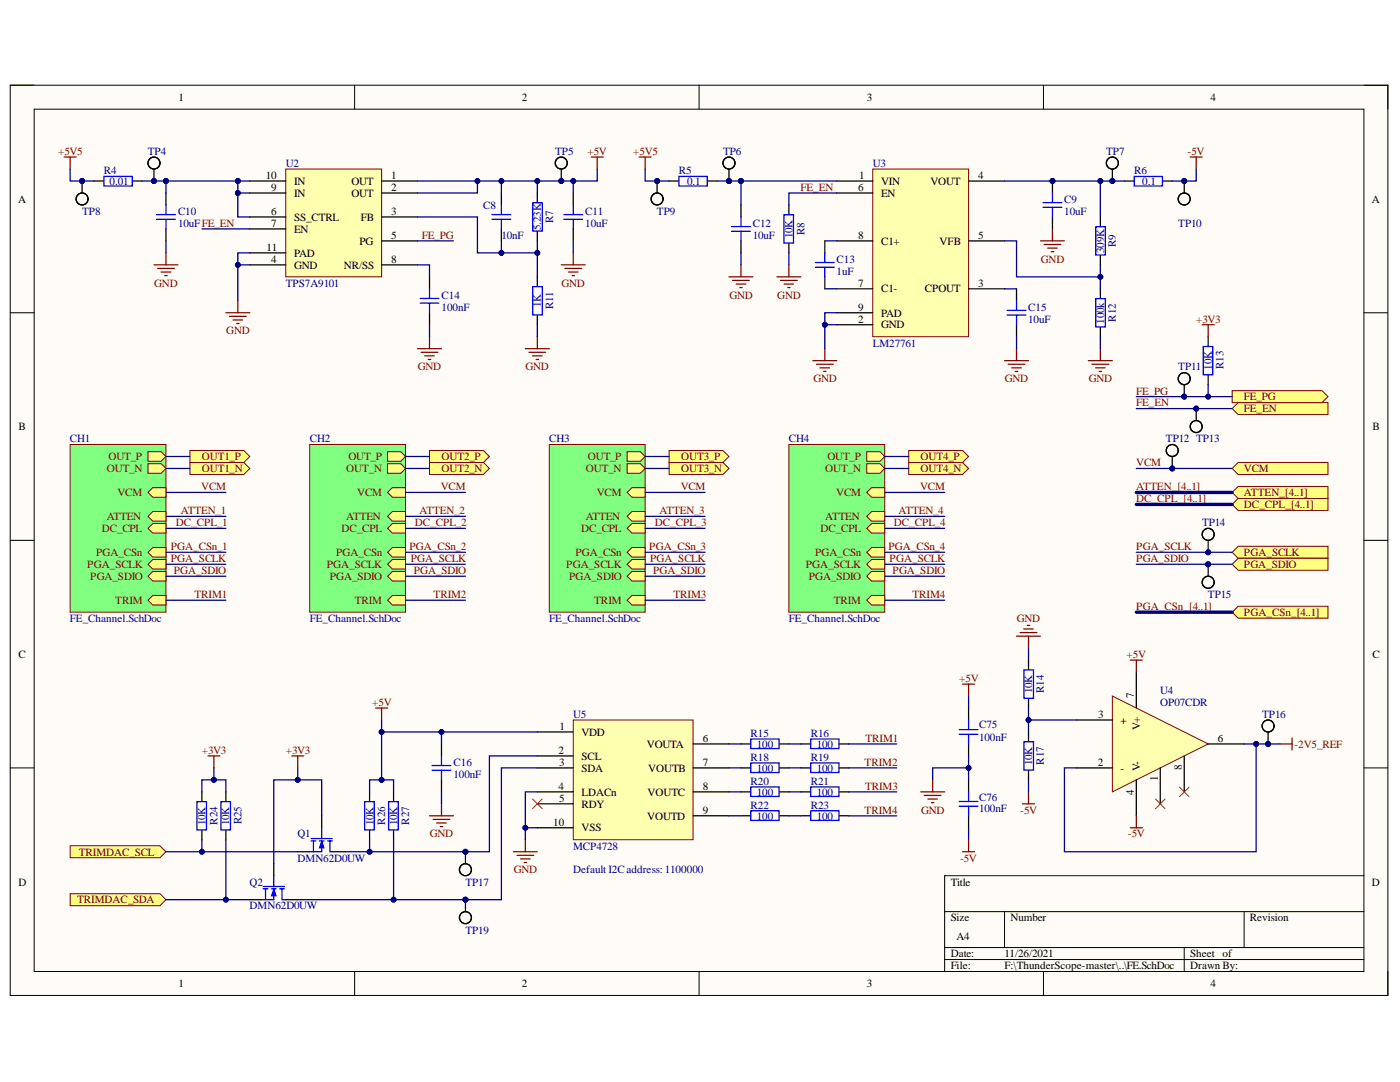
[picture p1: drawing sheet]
<svg xmlns="http://www.w3.org/2000/svg" width="279mm" height="216mm" viewBox="0 0 279 216" stroke-linecap="round" stroke-linejoin="round" font-family="sans-serif">
<defs><g id="words">
<g font-size="2.2">
<text x="35.6" y="20.1">1</text>
<text x="104.1" y="20.1">2</text>
<text x="173" y="20.1">3</text>
<text x="241.6" y="20.1">4</text>
<text x="53" y="35.7">10</text>
<text x="78.1" y="35.7">1</text>
<text x="171.5" y="35.7">1</text>
<text x="195.2" y="35.7">4</text>
<text x="3.6" y="40.4">A</text>
<text x="54.1" y="38.1">9</text>
<text x="58.7" y="39.2">IN</text>
<text x="58.7" y="36.9">IN</text>
<text x="70.1" y="36.9">OUT</text>
<text x="70.1" y="39.2">OUT</text>
<text x="78.1" y="38.1">2</text>
<text x="171.3" y="38.1">6</text>
<text x="175.9" y="36.9">VIN</text>
<text x="175.9" y="39.2">EN</text>
<text x="185.7" y="36.9">VOUT</text>
<text x="273.8" y="40.4">A</text>
<text x="54.1" y="42.9">6</text>
<text x="54.1" y="45.2">7</text>
<text x="58.7" y="44.1">SS_CTRL</text>
<text x="58.7" y="46.4">EN</text>
<text x="72" y="44.1">FB</text>
<text x="78.1" y="42.9">3</text>
<text x="78.1" y="47.6">5</text>
<text x="171.3" y="47.6">8</text>
<text x="195.2" y="47.6">5</text>
<text x="53.2" y="50.1">11</text>
<text x="54.1" y="52.4">4</text>
<text x="58.7" y="53.6">GND</text>
<text x="58.7" y="51.2">PAD</text>
<text x="68.6" y="53.6">NR/SS</text>
<text x="71.7" y="48.8">PG</text>
<text x="78.1" y="52.4">8</text>
<text x="175.9" y="48.8">C1+</text>
<text x="187.5" y="48.8">VFB</text>
<text x="171.3" y="57.2">7</text>
<text x="175.9" y="58.4">C1-</text>
<text x="184.6" y="58.4">CPOUT</text>
<text x="195.2" y="57.2">3</text>
<text x="171.3" y="64.4">2</text>
<text x="171.3" y="62">9</text>
<text x="175.9" y="65.5">GND</text>
<text x="175.9" y="63.2">PAD</text>
<text x="3.7" y="85.8">B</text>
<text x="273.9" y="85.8">B</text>
<text x="3.7" y="131.3">C</text>
<text x="273.9" y="131.3">C</text>
<text x="219.2" y="143.2">3</text>
<text x="226.3" y="139.4" transform="rotate(-90 226.3 139.4)">7</text>
<text x="111.7" y="145.6">1</text>
<text x="116.1" y="146.8">VDD</text>
<text x="129.1" y="149.2">VOUTA</text>
<text x="140.2" y="148">6</text>
<text x="223.6" y="144.4">+</text>
<text x="227.5" y="145.7" transform="rotate(-90 227.5 145.7)">V+</text>
<text x="243" y="148">6</text>
<text x="111.5" y="150.4">2</text>
<text x="111.6" y="152.8">3</text>
<text x="116.1" y="151.6">SCL</text>
<text x="116.1" y="154">SDA</text>
<text x="129.3" y="154">VOUTB</text>
<text x="140.2" y="152.8">7</text>
<text x="219.1" y="152.8">2</text>
<text x="223.6" y="154">-</text>
<text x="227.5" y="153.9" transform="rotate(-90 227.5 153.9)">V-</text>
<text x="231.1" y="155.9" transform="rotate(-90 231.1 155.9)">1</text>
<text x="235.8" y="153.7" transform="rotate(-90 235.8 153.7)">8</text>
<text x="111.5" y="157.5">4</text>
<text x="111.6" y="160">5</text>
<text x="116.1" y="158.8">LDACn</text>
<text x="116.1" y="161.2">RDY</text>
<text x="129.2" y="158.8">VOUTC</text>
<text x="140.2" y="157.5">8</text>
<text x="226.3" y="158.6" transform="rotate(-90 226.3 158.6)">4</text>
<text x="110.4" y="164.7">10</text>
<text x="116.1" y="165.9">VSS</text>
<text x="129.2" y="163.5">VOUTD</text>
<text x="140.2" y="162.4">9</text>
<text x="3.7" y="176.7">D</text>
<text x="189.7" y="176.7">Title</text>
<text x="273.8" y="176.7">D</text>
<text x="189.7" y="183.8">Size</text>
<text x="201.7" y="183.8">Number</text>
<text x="249.4" y="183.8">Revision</text>
<text x="189.7" y="191">Date:</text>
<text x="190.9" y="187.5">A4</text>
<text x="200.5" y="191">11/26/2021</text>
<text x="237.5" y="191">Sheet of</text>
<text x="35.6" y="197">1</text>
<text x="104.1" y="197">2</text>
<text x="173" y="197">3</text>
<text x="189.7" y="193.4">File:</text>
<text x="200.5" y="193.4">F:\ThunderScope-master\..\FE.SchDoc</text>
<text x="237.5" y="193.4">Drawn By:</text>
<text x="241.6" y="197">4</text>
</g>
<g font-size="2.2" fill="#800000">
<text x="11.6" y="30.9">+5V5</text>
<text x="117.2" y="30.9">+5V</text>
<text x="126.4" y="30.9">+5V5</text>
<text x="237" y="30.9">-5V</text>
<text x="159.8" y="38.1">FE_EN</text>
<text x="84.2" y="47.6">FE_PG</text>
<text x="207.7" y="52.4">GND</text>
<text x="30.8" y="57.2">GND</text>
<text x="112.1" y="57.2">GND</text>
<text x="145.6" y="59.6">GND</text>
<text x="155.1" y="59.6">GND</text>
<text x="238.7" y="64.4">+3V3</text>
<text x="45.2" y="66.7">GND</text>
<text x="83.4" y="73.9">GND</text>
<text x="104.9" y="73.9">GND</text>
<text x="162.3" y="76.3">GND</text>
<text x="200.6" y="76.3">GND</text>
<text x="217.3" y="76.3">GND</text>
<text x="226.8" y="81.1">FE_EN</text>
<text x="226.8" y="78.7">FE_PG</text>
<text x="248.3" y="82.3">FE_EN</text>
<text x="248.3" y="79.9">FE_PG</text>
<text x="21.3" y="94.2">OUT_N</text>
<text x="21.7" y="91.8">OUT_P</text>
<text x="40.3" y="94.2">OUT1_N</text>
<text x="40.3" y="91.8">OUT1_P</text>
<text x="69.1" y="94.2">OUT_N</text>
<text x="69.5" y="91.8">OUT_P</text>
<text x="88.1" y="94.2">OUT2_N</text>
<text x="88.1" y="91.8">OUT2_P</text>
<text x="116.9" y="94.2">OUT_N</text>
<text x="117.3" y="91.8">OUT_P</text>
<text x="135.9" y="94.2">OUT3_N</text>
<text x="135.9" y="91.8">OUT3_P</text>
<text x="164.7" y="94.2">OUT_N</text>
<text x="165.1" y="91.8">OUT_P</text>
<text x="183.7" y="94.2">OUT4_N</text>
<text x="183.7" y="91.8">OUT4_P</text>
<text x="226.8" y="93">VCM</text>
<text x="248.3" y="94.2">VCM</text>
<text x="23.4" y="99">VCM</text>
<text x="40.2" y="97.8">VCM</text>
<text x="71.3" y="99">VCM</text>
<text x="88" y="97.8">VCM</text>
<text x="119.1" y="99">VCM</text>
<text x="135.8" y="97.8">VCM</text>
<text x="166.9" y="99">VCM</text>
<text x="183.6" y="97.8">VCM</text>
<text x="226.8" y="97.8">ATTEN_[4..1]</text>
<text x="226.8" y="100.2">DC_CPL_[4..1]</text>
<text x="248.3" y="99">ATTEN_[4..1]</text>
<text x="248.3" y="101.4">DC_CPL_[4..1]</text>
<text x="20.3" y="106.2">DC_CPL</text>
<text x="21.3" y="103.8">ATTEN</text>
<text x="35.1" y="105">DC_CPL_1</text>
<text x="36.1" y="102.6">ATTEN_1</text>
<text x="68.2" y="106.2">DC_CPL</text>
<text x="69.1" y="103.8">ATTEN</text>
<text x="82.8" y="105">DC_CPL_2</text>
<text x="83.7" y="102.6">ATTEN_2</text>
<text x="116" y="106.2">DC_CPL</text>
<text x="116.9" y="103.8">ATTEN</text>
<text x="130.7" y="105">DC_CPL_3</text>
<text x="131.6" y="102.6">ATTEN_3</text>
<text x="163.8" y="106.2">DC_CPL</text>
<text x="164.7" y="103.8">ATTEN</text>
<text x="178.4" y="105">DC_CPL_4</text>
<text x="179.3" y="102.6">ATTEN_4</text>
<text x="17.4" y="113.4">PGA_SCLK</text>
<text x="19.2" y="110.9">PGA_CSn</text>
<text x="34.1" y="112.1">PGA_SCLK</text>
<text x="34.1" y="109.8">PGA_CSn_1</text>
<text x="65.2" y="113.4">PGA_SCLK</text>
<text x="67.1" y="110.9">PGA_CSn</text>
<text x="81.7" y="109.8">PGA_CSn_2</text>
<text x="82" y="112.1">PGA_SCLK</text>
<text x="113" y="113.4">PGA_SCLK</text>
<text x="114.9" y="110.9">PGA_CSn</text>
<text x="129.6" y="109.8">PGA_CSn_3</text>
<text x="129.8" y="112.1">PGA_SCLK</text>
<text x="160.8" y="113.4">PGA_SCLK</text>
<text x="162.7" y="110.9">PGA_CSn</text>
<text x="177.3" y="109.8">PGA_CSn_4</text>
<text x="177.5" y="112.1">PGA_SCLK</text>
<text x="226.8" y="109.8">PGA_SCLK</text>
<text x="226.8" y="112.1">PGA_SDIO</text>
<text x="248.3" y="110.9">PGA_SCLK</text>
<text x="248.3" y="113.4">PGA_SDIO</text>
<text x="18" y="115.8">PGA_SDIO</text>
<text x="34.7" y="114.6">PGA_SDIO</text>
<text x="38.8" y="119.3">TRIM1</text>
<text x="65.8" y="115.8">PGA_SDIO</text>
<text x="82.6" y="114.6">PGA_SDIO</text>
<text x="86.5" y="119.3">TRIM2</text>
<text x="113.6" y="115.8">PGA_SDIO</text>
<text x="130.3" y="114.6">PGA_SDIO</text>
<text x="134.4" y="119.3">TRIM3</text>
<text x="161.4" y="115.8">PGA_SDIO</text>
<text x="178.1" y="114.6">PGA_SDIO</text>
<text x="182.1" y="119.3">TRIM4</text>
<text x="23" y="120.5">TRIM</text>
<text x="70.8" y="120.5">TRIM</text>
<text x="118.6" y="120.5">TRIM</text>
<text x="166.4" y="120.5">TRIM</text>
<text x="202.9" y="124.1">GND</text>
<text x="226.8" y="121.7">PGA_CSn_[4..1]</text>
<text x="248.3" y="123">PGA_CSn_[4..1]</text>
<text x="224.8" y="131.3">+5V</text>
<text x="191.4" y="136.1">+5V</text>
<text x="74.3" y="140.9">+5V</text>
<text x="172.7" y="148">TRIM1</text>
<text x="258.3" y="149.2">-2V5_REF</text>
<text x="40.3" y="150.4">+3V3</text>
<text x="57" y="150.4">+3V3</text>
<text x="172.6" y="152.8">TRIM2</text>
<text x="172.6" y="157.5">TRIM3</text>
<text x="85.8" y="167.1">GND</text>
<text x="172.6" y="162.4">TRIM4</text>
<text x="183.8" y="162.4">GND</text>
<text x="203.6" y="162.4">-5V</text>
<text x="225.1" y="167.1">-5V</text>
<text x="15.7" y="170.7">TRIMDAC_SCL</text>
<text x="191.6" y="171.9">-5V</text>
<text x="102.5" y="174.3">GND</text>
<text x="15.4" y="180.3">TRIMDAC_SDA</text>
</g>
<g font-size="2.2" fill="#000080">
<text x="20.7" y="34.8">R4</text>
<text x="29.5" y="30.9">TP4</text>
<text x="57" y="33.3">U2</text>
<text x="110.8" y="30.9">TP5</text>
<text x="135.5" y="34.8">R5</text>
<text x="144.3" y="30.9">TP6</text>
<text x="174.2" y="33.3">U3</text>
<text x="220.8" y="30.9">TP7</text>
<text x="226.4" y="34.8">R6</text>
<text x="21.8" y="36.9">0.01</text>
<text x="96.4" y="41.7">C8</text>
<text x="137.1" y="36.9">0.1</text>
<text x="212.4" y="40.4">C9</text>
<text x="228" y="36.9">0.1</text>
<text x="16.4" y="42.9">TP8</text>
<text x="35.5" y="42.9">C10</text>
<text x="35.5" y="45.2">10uFFE_EN</text>
<text x="100.1" y="47.6">10nF</text>
<text x="107.9" y="45.9" transform="rotate(-90 107.9 45.9)">5.23K</text>
<text x="110.4" y="44.5" transform="rotate(-90 110.4 44.5)">R7</text>
<text x="116.8" y="42.9">C11</text>
<text x="116.8" y="45.2">10uF</text>
<text x="131.1" y="42.9">TP9</text>
<text x="150.2" y="45.2">C12</text>
<text x="150.2" y="47.6">10uF</text>
<text x="158.2" y="47.5" transform="rotate(-90 158.2 47.5)">10K</text>
<text x="160.5" y="46.9" transform="rotate(-90 160.5 46.9)">R8</text>
<text x="212.4" y="42.9">10uF</text>
<text x="235.2" y="45.2">TP10</text>
<text x="167" y="52.4">C13</text>
<text x="220.3" y="50.5" transform="rotate(-90 220.3 50.5)">309K</text>
<text x="222.7" y="49.3" transform="rotate(-90 222.7 49.3)">R9</text>
<text x="57" y="57.2">TPS7A9101</text>
<text x="88.1" y="59.6">C14</text>
<text x="167" y="54.8">1uF</text>
<text x="88.1" y="62">100nF</text>
<text x="107.9" y="61.3" transform="rotate(-90 107.9 61.3)">1K</text>
<text x="110.4" y="61.6" transform="rotate(-90 110.4 61.6)">R11</text>
<text x="205.2" y="62">C15</text>
<text x="205.2" y="64.4">10uF</text>
<text x="220.3" y="64.6" transform="rotate(-90 220.3 64.6)">100k</text>
<text x="222.7" y="64.2" transform="rotate(-90 222.7 64.2)">R12</text>
<text x="174.2" y="69.2">LM27761</text>
<text x="235.2" y="73.9">TP11</text>
<text x="241.8" y="73.8" transform="rotate(-90 241.8 73.8)">10K</text>
<text x="244.2" y="73.7" transform="rotate(-90 244.2 73.7)">R13</text>
<text x="14" y="88.3">CH1</text>
<text x="61.8" y="88.3">CH2</text>
<text x="109.6" y="88.3">CH3</text>
<text x="157.4" y="88.3">CH4</text>
<text x="232.7" y="88.3">TP12 TP13</text>
<text x="239.9" y="105">TP14</text>
<text x="241.1" y="119.3">TP15</text>
<text x="14" y="124.1">FE_Channel.SchDoc</text>
<text x="61.8" y="124.1">FE_Channel.SchDoc</text>
<text x="109.6" y="124.1">FE_Channel.SchDoc</text>
<text x="157.4" y="124.1">FE_Channel.SchDoc</text>
<text x="114.4" y="143.2">U5</text>
<text x="206" y="138.3" transform="rotate(-90 206 138.3)">10K</text>
<text x="208.3" y="138.3" transform="rotate(-90 208.3 138.3)">R14</text>
<text x="231.5" y="138.4">U4</text>
<text x="231.5" y="140.9">OP07CDR</text>
<text x="251.9" y="143.2">TP16</text>
<text x="149.8" y="147.1">R15</text>
<text x="151.1" y="149.2">100</text>
<text x="161.8" y="147.1">R16</text>
<text x="163" y="149.2">100</text>
<text x="195.4" y="145.4">C75</text>
<text x="195.4" y="147.8">100nF</text>
<text x="90.5" y="152.8">C16</text>
<text x="90.5" y="155.2">100nF</text>
<text x="149.8" y="151.8">R18</text>
<text x="151.1" y="154">100</text>
<text x="161.8" y="151.8">R19</text>
<text x="163" y="154">100</text>
<text x="206" y="152.7" transform="rotate(-90 206 152.7)">10K</text>
<text x="208.3" y="152.5" transform="rotate(-90 208.3 152.5)">R17</text>
<text x="149.8" y="156.6">R20</text>
<text x="149.8" y="161.3">R22</text>
<text x="151.1" y="158.8">100</text>
<text x="161.8" y="156.6">R21</text>
<text x="161.8" y="161.3">R23</text>
<text x="163" y="158.8">100</text>
<text x="195.4" y="159.7">C76</text>
<text x="41" y="164.6" transform="rotate(-90 41 164.6)">10K</text>
<text x="43.4" y="164.6" transform="rotate(-90 43.4 164.6)">R24</text>
<text x="45.8" y="164.6" transform="rotate(-90 45.8 164.6)">10K</text>
<text x="48.2" y="164.5" transform="rotate(-90 48.2 164.5)">R25</text>
<text x="59.4" y="167.1">Q1</text>
<text x="74.5" y="164.6" transform="rotate(-90 74.5 164.6)">10K</text>
<text x="76.9" y="164.6" transform="rotate(-90 76.9 164.6)">R26</text>
<text x="79.3" y="164.6" transform="rotate(-90 79.3 164.6)">10K</text>
<text x="81.6" y="164.6" transform="rotate(-90 81.6 164.6)">R27</text>
<text x="151.1" y="163.5">100</text>
<text x="163" y="163.5">100</text>
<text x="195.4" y="162.1">100nF</text>
<text x="59.4" y="171.9">DMN62D0UW</text>
<text x="114.4" y="169.5">MCP4728</text>
<text x="49.8" y="176.7">Q2</text>
<text x="92.9" y="176.7">TP17</text>
<text x="114.4" y="174.3">Default I2Caddress: 1100000</text>
<text x="49.8" y="181.5">DMN62D0UW</text>
<text x="92.9" y="186.3">TP19</text>
</g>
</g></defs>
<path d="M2 17h275v181.6h-275z" fill-rule="evenodd" fill="#fffcf8"/>
<path d="M2 17h275v181.6h-275z" fill="none" stroke="#000" stroke-width=".2"/>
<path d="M6.8 21.8h265.4v172.1h-265.4z" fill-rule="evenodd" fill="#fffcf8"/>
<g fill="none" stroke="#000" stroke-width=".2">
<path d="M2 17h4.8M70.8 17v4.8M139.5 17v4.8M208.2 17v4.8M272.2 17h4.8v4.8M6.8 21.8h265.4v172.1h-265.4zM2 62.4h4.8M272.2 62.4h4.8M2 107.8h4.8M272.2 107.8h4.8M2 153.2h4.8M272.2 153.2h4.8"/>
<path d="M272.2 174.7h-83.7v19.2M70.8 193.9v4.7M139.5 193.9v4.7M188.5 181.9h83.7M188.5 189.1h83.7M188.5 191.5h83.7M200.5 181.9v7.2M208.2 193.9v4.7M236.3 189.1v4.8M248.3 181.9v7.2M277 193.9v4.7"/>
</g>
<path d="M14 88.7h19.1v33.5h-19.1z" fill-rule="evenodd" fill="#80ff80"/>
<path d="M14 88.7h19.1v33.5h-19.1z" fill="none" stroke="#800000" stroke-width=".2"/>
<path d="M29.5 90.1h2.7l.9 1-.9 .9h-2.7z" fill-rule="evenodd" fill="#ffff80"/>
<path d="M29.5 90.1h2.7l.9 1-.9 .9h-2.7z" fill="none" stroke="#800000" stroke-width=".2"/>
<path d="M29.5 98.3l1-1h2.6v1.9h-2.6z" fill-rule="evenodd" fill="#ffff80"/>
<path d="M29.5 98.3l1-1h2.6v1.9h-2.6z" fill="none" stroke="#800000" stroke-width=".2"/>
<path d="M29.5 92.5h2.7l.9 1-.9 .9h-2.7z" fill-rule="evenodd" fill="#ffff80"/>
<path d="M29.5 92.5h2.7l.9 1-.9 .9h-2.7z" fill="none" stroke="#800000" stroke-width=".2"/>
<path d="M29.5 119.8l1-1h2.6v1.9h-2.6z" fill-rule="evenodd" fill="#ffff80"/>
<path d="M29.5 119.8l1-1h2.6v1.9h-2.6z" fill="none" stroke="#800000" stroke-width=".2"/>
<path d="M29.5 103l1-.9h2.6v1.9h-2.6z" fill-rule="evenodd" fill="#ffff80"/>
<path d="M29.5 103l1-.9h2.6v1.9h-2.6z" fill="none" stroke="#800000" stroke-width=".2"/>
<path d="M29.5 105.4l1-.9h2.6v1.9h-2.6z" fill-rule="evenodd" fill="#ffff80"/>
<path d="M29.5 105.4l1-.9h2.6v1.9h-2.6z" fill="none" stroke="#800000" stroke-width=".2"/>
<path d="M29.5 110.2l1-1h2.6v2h-2.6z" fill-rule="evenodd" fill="#ffff80"/>
<path d="M29.5 110.2l1-1h2.6v2h-2.6z" fill="none" stroke="#800000" stroke-width=".2"/>
<path d="M29.5 112.6l1-1h2.6v2h-2.6z" fill-rule="evenodd" fill="#ffff80"/>
<path d="M29.5 112.6l1-1h2.6v2h-2.6z" fill="none" stroke="#800000" stroke-width=".2"/>
<path d="M29.5 115l1-1h2.6v1.9h-2.6z" fill-rule="evenodd" fill="#ffff80"/>
<path d="M29.5 115l1-1h2.6v1.9h-2.6z" fill="none" stroke="#800000" stroke-width=".2"/>
<path d="M88.1 148.4v2.4M88.1 155.6v2.4M147.9 148.4h1.9M155.6 148.4h1.8M159.8 148.4h1.9M167.5 148.4h1.9M59.4 170h2.4M64.2 162.8v2.4M66.6 170h2.4" fill="none" stroke="#000" stroke-width=".25"/>
<g fill="none" stroke="#00f" stroke-width=".25">
<path d="M86.2 153.7h3.8M86.2 152.8h3.8M88.1 150.8v2M88.1 153.7v1.9M149.8 147.5h5.7v1.9h-5.7zM161.8 147.5h5.6v1.9h-5.6zM62.1 167.3h4.2M62.1 167.8h.9M62.6 167.8v2.2M63.7 167.8h1M64.2 165.2v2.1M64.2 167.8v2.2h-2.4"/>
<path d="M65.4 167.8h.9M65.8 167.8v2.2"/>
</g>
<path d="M85.7 162.8h4.8M86.4 163.5h3.4M87.2 164.2h1.9M87.9 164.9h.4M88.1 160.4v2.4M102.5 170h4.7M103.2 170.7h3.3M103.9 171.4h1.9M104.6 172.1h.5M104.8 167.6v2.4" fill="none" stroke="#800000" stroke-width=".25"/>
<path d="M64.2 167.8l.5 1.4h-1z" fill="#00f"/>
<path d="M64.2 167.8l.5 1.4h-1z" fill="none" stroke="#00f" stroke-width=".2"/>
<path d="M52.5 176.9h4.3M52.5 177.4h1M53 177.4v2.1M54.2 177.4h.9M54.6 174.7v2.2M54.6 177.4v2.1h-2.4M55.8 177.4h1M56.3 177.4v2.1M65.9 170h.7" fill="none" stroke="#00f" stroke-width=".25"/>
<path d="M49.9 179.5h2.3M54.6 172.3v2.4M57 179.5h2.4" fill="none" stroke="#000" stroke-width=".25"/>
<path d="M54.6 177.4l.5 1.4h-.9z" fill="#00f"/>
<path d="M54.6 177.4l.5 1.4h-.9z" fill="none" stroke="#00f" stroke-width=".2"/>
<path d="M39.3 160h1.9v5.6h-1.9zM44.1 160h1.9v5.6h-1.9zM72.8 160h1.9v5.6h-1.9zM77.6 160h1.9v5.6h-1.9zM56.3 179.5h.7" fill="none" stroke="#00f" stroke-width=".25"/>
<path d="M40.3 158v1.9M45.1 158v1.9M73.8 158v1.9M78.5 158v1.9M40.3 165.7v1.9M45.1 165.7v1.9M73.8 165.7v1.9M78.5 165.7v1.9" fill="none" stroke="#000" stroke-width=".25"/>
<path d="M41.5 150.8h2.4M42.7 150.8v2.4M58.2 150.8h2.4M59.4 150.8v2.4M75 141.3h2.3M76.2 141.3v2.4" fill="none" stroke="#800000" stroke-width=".25"/>
<path d="M14 168.8h17.9l1.2 1.2-1.2 1.2h-17.9z" fill-rule="evenodd" fill="#ffff80"/>
<path d="M14 168.8h17.9l1.2 1.2-1.2 1.2h-17.9z" fill="none" stroke="#800000" stroke-width=".2"/>
<path d="M14 178.3h17.9l1.2 1.2-1.2 1.2h-17.9z" fill-rule="evenodd" fill="#ffff80"/>
<path d="M14 178.3h17.9l1.2 1.2-1.2 1.2h-17.9z" fill="none" stroke="#800000" stroke-width=".2"/>
<path d="M222 138.9l19.1 9.5-19.1 9.6z" fill="#ffffb0"/>
<path d="M222 138.9l19.1 9.5-19.1 9.6z" fill="none" stroke="#800000" stroke-width=".2"/>
<path d="M205.3 131.7v1.9M205.3 139.4v1.9M226.8 134.1v7.2M205.3 146.1v1.8M205.3 153.7v1.9M214.8 143.7h7.2M214.8 153.2h7.2M226.8 155.6v7.2M231.6 153.2v7.2M236.3 150.8v7.2M241.1 148.4h7.2" fill="none" stroke="#000" stroke-width=".25"/>
<g fill="none" stroke="#800000" stroke-width=".25">
<path d="M202.9 126.9h4.8M203.6 126.2h3.3M204.3 125.5h1.9M205 124.8h.5M205.3 126.9v2.4M225.6 131.7h2.4M226.8 131.7v2.4M205.3 158v2.4M255.5 148.4h2.4M257.9 147.3v2.3M204.1 160.4h2.4M225.6 165.2h2.4"/>
<path d="M226.8 162.8v2.4"/>
</g>
<path d="M230.6 159.4l1.9 2M232.5 159.4l-1.9 2M235.4 157.1l1.9 1.9M237.3 157.1l-1.9 1.9" fill="none" stroke="#f00" stroke-width=".2"/>
<path d="M204.3 133.7h2v5.6h-2zM204.3 148h2v5.7h-2z" fill="none" stroke="#00f" stroke-width=".25"/>
<path d="M61.8 88.7h19.1v33.5h-19.1z" fill-rule="evenodd" fill="#80ff80"/>
<path d="M61.8 88.7h19.1v33.5h-19.1z" fill="none" stroke="#800000" stroke-width=".2"/>
<path d="M77.3 90.1h2.7l.9 1-.9 .9h-2.7z" fill-rule="evenodd" fill="#ffff80"/>
<path d="M77.3 90.1h2.7l.9 1-.9 .9h-2.7z" fill="none" stroke="#800000" stroke-width=".2"/>
<path d="M77.3 98.3l1-1h2.6v1.9h-2.6z" fill-rule="evenodd" fill="#ffff80"/>
<path d="M77.3 98.3l1-1h2.6v1.9h-2.6z" fill="none" stroke="#800000" stroke-width=".2"/>
<path d="M77.3 92.5h2.7l.9 1-.9 .9h-2.7z" fill-rule="evenodd" fill="#ffff80"/>
<path d="M77.3 92.5h2.7l.9 1-.9 .9h-2.7z" fill="none" stroke="#800000" stroke-width=".2"/>
<path d="M77.3 119.8l1-1h2.6v1.9h-2.6z" fill-rule="evenodd" fill="#ffff80"/>
<path d="M77.3 119.8l1-1h2.6v1.9h-2.6z" fill="none" stroke="#800000" stroke-width=".2"/>
<path d="M77.3 103l1-.9h2.6v1.9h-2.6z" fill-rule="evenodd" fill="#ffff80"/>
<path d="M77.3 103l1-.9h2.6v1.9h-2.6z" fill="none" stroke="#800000" stroke-width=".2"/>
<path d="M77.3 105.4l1-.9h2.6v1.9h-2.6z" fill-rule="evenodd" fill="#ffff80"/>
<path d="M77.3 105.4l1-.9h2.6v1.9h-2.6z" fill="none" stroke="#800000" stroke-width=".2"/>
<path d="M77.3 110.2l1-1h2.6v2h-2.6z" fill-rule="evenodd" fill="#ffff80"/>
<path d="M77.3 110.2l1-1h2.6v2h-2.6z" fill="none" stroke="#800000" stroke-width=".2"/>
<path d="M77.3 112.6l1-1h2.6v2h-2.6z" fill-rule="evenodd" fill="#ffff80"/>
<path d="M77.3 112.6l1-1h2.6v2h-2.6z" fill="none" stroke="#800000" stroke-width=".2"/>
<path d="M77.3 115l1-1h2.6v1.9h-2.6z" fill-rule="evenodd" fill="#ffff80"/>
<path d="M77.3 115l1-1h2.6v1.9h-2.6z" fill="none" stroke="#800000" stroke-width=".2"/>
<path d="M109.6 88.7h19.2v33.5h-19.2z" fill-rule="evenodd" fill="#80ff80"/>
<path d="M109.6 88.7h19.2v33.5h-19.2z" fill="none" stroke="#800000" stroke-width=".2"/>
<path d="M125.2 90.1h2.6l1 1-1 .9h-2.6z" fill-rule="evenodd" fill="#ffff80"/>
<path d="M125.2 90.1h2.6l1 1-1 .9h-2.6z" fill="none" stroke="#800000" stroke-width=".2"/>
<path d="M125.2 98.3l.9-1h2.7v1.9h-2.7z" fill-rule="evenodd" fill="#ffff80"/>
<path d="M125.2 98.3l.9-1h2.7v1.9h-2.7z" fill="none" stroke="#800000" stroke-width=".2"/>
<path d="M125.2 92.5h2.6l1 1-1 .9h-2.6z" fill-rule="evenodd" fill="#ffff80"/>
<path d="M125.2 92.5h2.6l1 1-1 .9h-2.6z" fill="none" stroke="#800000" stroke-width=".2"/>
<path d="M125.2 119.8l.9-1h2.7v1.9h-2.7z" fill-rule="evenodd" fill="#ffff80"/>
<path d="M125.2 119.8l.9-1h2.7v1.9h-2.7z" fill="none" stroke="#800000" stroke-width=".2"/>
<path d="M125.2 103l.9-.9h2.7v1.9h-2.7z" fill-rule="evenodd" fill="#ffff80"/>
<path d="M125.2 103l.9-.9h2.7v1.9h-2.7z" fill="none" stroke="#800000" stroke-width=".2"/>
<path d="M125.2 105.4l.9-.9h2.7v1.9h-2.7z" fill-rule="evenodd" fill="#ffff80"/>
<path d="M125.2 105.4l.9-.9h2.7v1.9h-2.7z" fill="none" stroke="#800000" stroke-width=".2"/>
<path d="M125.2 110.2l.9-1h2.7v2h-2.7z" fill-rule="evenodd" fill="#ffff80"/>
<path d="M125.2 110.2l.9-1h2.7v2h-2.7z" fill="none" stroke="#800000" stroke-width=".2"/>
<path d="M125.2 112.6l.9-1h2.7v2h-2.7z" fill-rule="evenodd" fill="#ffff80"/>
<path d="M125.2 112.6l.9-1h2.7v2h-2.7z" fill="none" stroke="#800000" stroke-width=".2"/>
<path d="M125.2 115l.9-1h2.7v1.9h-2.7z" fill-rule="evenodd" fill="#ffff80"/>
<path d="M125.2 115l.9-1h2.7v1.9h-2.7z" fill="none" stroke="#800000" stroke-width=".2"/>
<path d="M157.4 88.7h19.2v33.5h-19.2z" fill-rule="evenodd" fill="#80ff80"/>
<path d="M157.4 88.7h19.2v33.5h-19.2z" fill="none" stroke="#800000" stroke-width=".2"/>
<path d="M173 90.1h2.6l1 1-1 .9h-2.6z" fill-rule="evenodd" fill="#ffff80"/>
<path d="M173 90.1h2.6l1 1-1 .9h-2.6z" fill="none" stroke="#800000" stroke-width=".2"/>
<path d="M173 98.3l.9-1h2.7v1.9h-2.7z" fill-rule="evenodd" fill="#ffff80"/>
<path d="M173 98.3l.9-1h2.7v1.9h-2.7z" fill="none" stroke="#800000" stroke-width=".2"/>
<path d="M173 92.5h2.6l1 1-1 .9h-2.6z" fill-rule="evenodd" fill="#ffff80"/>
<path d="M173 92.5h2.6l1 1-1 .9h-2.6z" fill="none" stroke="#800000" stroke-width=".2"/>
<path d="M173 119.8l.9-1h2.7v1.9h-2.7z" fill-rule="evenodd" fill="#ffff80"/>
<path d="M173 119.8l.9-1h2.7v1.9h-2.7z" fill="none" stroke="#800000" stroke-width=".2"/>
<path d="M173 103l.9-.9h2.7v1.9h-2.7z" fill-rule="evenodd" fill="#ffff80"/>
<path d="M173 103l.9-.9h2.7v1.9h-2.7z" fill="none" stroke="#800000" stroke-width=".2"/>
<path d="M173 105.4l.9-.9h2.7v1.9h-2.7z" fill-rule="evenodd" fill="#ffff80"/>
<path d="M173 105.4l.9-.9h2.7v1.9h-2.7z" fill="none" stroke="#800000" stroke-width=".2"/>
<path d="M173 110.2l.9-.9h2.7v1.9h-2.7z" fill-rule="evenodd" fill="#ffff80"/>
<path d="M173 110.2l.9-.9h2.7v1.9h-2.7z" fill="none" stroke="#800000" stroke-width=".2"/>
<path d="M173 112.6l.9-1h2.7v2h-2.7z" fill-rule="evenodd" fill="#ffff80"/>
<path d="M173 112.6l.9-1h2.7v2h-2.7z" fill="none" stroke="#800000" stroke-width=".2"/>
<path d="M173 115l.9-1h2.7v1.9h-2.7z" fill-rule="evenodd" fill="#ffff80"/>
<path d="M173 115l.9-1h2.7v1.9h-2.7z" fill="none" stroke="#800000" stroke-width=".2"/>
<path d="M114.4 143.7h23.9v23.9h-23.9z" fill-rule="evenodd" fill="#ffffb0"/>
<path d="M114.4 143.7h23.9v23.9h-23.9z" fill="none" stroke="#800000" stroke-width=".2"/>
<g fill="none" stroke="#000" stroke-width=".25">
<path d="M107.2 146.1h7.2M107.2 150.8h7.2M107.2 153.2h7.2M107.2 158h7.2M138.3 153.2h7.2M138.3 158h7.2M138.3 148.4h7.2M147.9 153.2h1.9M147.9 158h1.9M155.6 153.2h1.8M155.6 158h1.8M159.8 153.2h1.9"/>
<path d="M159.8 158h1.9M167.5 153.2h1.9M167.5 158h1.9M107.2 160.4h7.2M107.2 165.2h7.2M138.3 162.8h7.2M147.9 162.8h1.9M155.6 162.8h1.8M159.8 162.8h1.9M167.5 162.8h1.9"/>
</g>
<path d="M149.8 152.2h5.7v1.9h-5.7zM149.8 157h5.7v1.9h-5.7zM161.8 152.2h5.6v1.9h-5.6zM161.8 157h5.6v1.9h-5.6zM149.8 161.8h5.7v1.9h-5.7zM161.8 161.8h5.6v1.9h-5.6z" fill="none" stroke="#00f" stroke-width=".25"/>
<path d="M106.3 159.4l1.9 2M108.2 159.4l-1.9 2" fill="none" stroke="#f00" stroke-width=".2"/>
<path d="M245.9 98.3l1.2-1.2h17.9v2.4h-17.9z" fill-rule="evenodd" fill="#ffff80"/>
<path d="M245.9 98.3l1.2-1.2h17.9v2.4h-17.9z" fill="none" stroke="#800000" stroke-width=".2"/>
<path d="M245.9 100.7l1.2-1.2h17.9v2.3h-17.9z" fill-rule="evenodd" fill="#ffff80"/>
<path d="M245.9 100.7l1.2-1.2h17.9v2.3h-17.9z" fill="none" stroke="#800000" stroke-width=".2"/>
<path d="M245.9 110.2l1.2-1.2h17.9v2.4h-17.9z" fill-rule="evenodd" fill="#ffff80"/>
<path d="M245.9 110.2l1.2-1.2h17.9v2.4h-17.9z" fill="none" stroke="#800000" stroke-width=".2"/>
<path d="M245.9 112.6l1.2-1.2h17.9v2.4h-17.9z" fill-rule="evenodd" fill="#ffff80"/>
<path d="M245.9 112.6l1.2-1.2h17.9v2.4h-17.9z" fill="none" stroke="#800000" stroke-width=".2"/>
<path d="M245.9 122.2l1.2-1.2h17.9v2.4h-17.9z" fill-rule="evenodd" fill="#ffff80"/>
<path d="M245.9 122.2l1.2-1.2h17.9v2.4h-17.9z" fill="none" stroke="#800000" stroke-width=".2"/>
<path d="M245.9 93.5l1.2-1.2h17.9v2.4h-17.9z" fill-rule="evenodd" fill="#ffff80"/>
<path d="M245.9 93.5l1.2-1.2h17.9v2.4h-17.9z" fill="none" stroke="#800000" stroke-width=".2"/>
<path d="M37.9 92.3h10.8l1.2 1.2-1.2 1.2h-10.8z" fill-rule="evenodd" fill="#ffff80"/>
<path d="M37.9 92.3h10.8l1.2 1.2-1.2 1.2h-10.8z" fill="none" stroke="#800000" stroke-width=".2"/>
<path d="M37.9 89.9h10.8l1.2 1.2-1.2 1.2h-10.8z" fill-rule="evenodd" fill="#ffff80"/>
<path d="M37.9 89.9h10.8l1.2 1.2-1.2 1.2h-10.8z" fill="none" stroke="#800000" stroke-width=".2"/>
<path d="M85.7 92.3h10.8l1.2 1.2-1.2 1.2h-10.8z" fill-rule="evenodd" fill="#ffff80"/>
<path d="M85.7 92.3h10.8l1.2 1.2-1.2 1.2h-10.8z" fill="none" stroke="#800000" stroke-width=".2"/>
<path d="M85.7 89.9h10.8l1.2 1.2-1.2 1.2h-10.8z" fill-rule="evenodd" fill="#ffff80"/>
<path d="M85.7 89.9h10.8l1.2 1.2-1.2 1.2h-10.8z" fill="none" stroke="#800000" stroke-width=".2"/>
<path d="M133.5 92.3h10.8l1.2 1.2-1.2 1.2h-10.8z" fill-rule="evenodd" fill="#ffff80"/>
<path d="M133.5 92.3h10.8l1.2 1.2-1.2 1.2h-10.8z" fill="none" stroke="#800000" stroke-width=".2"/>
<path d="M133.5 89.9h10.8l1.2 1.2-1.2 1.2h-10.8z" fill-rule="evenodd" fill="#ffff80"/>
<path d="M133.5 89.9h10.8l1.2 1.2-1.2 1.2h-10.8z" fill="none" stroke="#800000" stroke-width=".2"/>
<path d="M181.4 92.3h10.7l1.2 1.2-1.2 1.2h-10.7z" fill-rule="evenodd" fill="#ffff80"/>
<path d="M181.4 92.3h10.7l1.2 1.2-1.2 1.2h-10.7z" fill="none" stroke="#800000" stroke-width=".2"/>
<path d="M181.4 89.9h10.7l1.2 1.2-1.2 1.2h-10.7z" fill-rule="evenodd" fill="#ffff80"/>
<path d="M181.4 89.9h10.7l1.2 1.2-1.2 1.2h-10.7z" fill="none" stroke="#800000" stroke-width=".2"/>
<path d="M245.9 81.5l1.2-1.2h17.9v2.4h-17.9z" fill-rule="evenodd" fill="#ffff80"/>
<path d="M245.9 81.5l1.2-1.2h17.9v2.4h-17.9z" fill="none" stroke="#800000" stroke-width=".2"/>
<path d="M174.2 33.7h19.1v33.5h-19.1z" fill-rule="evenodd" fill="#ffffb0"/>
<path d="M174.2 33.7h19.1v33.5h-19.1z" fill="none" stroke="#800000" stroke-width=".2"/>
<g fill="none" stroke="#000" stroke-width=".25">
<path d="M167 36.1h7.2M167 38.5h7.2M193.3 36.1h7.2M147.9 40.9v2.4M147.9 48.1v2.4M164.6 48.1v2.4M164.6 55.2v2.4M167 57.6h7.2M167 48.1h7.2M193.3 57.6h7.2M193.3 48.1h7.2M202.9 57.6v2.4"/>
<path d="M219.6 43.3v1.9M219.6 51v1.9M219.6 57.6v1.9M167 64.8h7.2M167 62.4h7.2M202.9 64.8v2.4M219.6 65.3v1.9"/>
</g>
<g fill="none" stroke="#00f" stroke-width=".25">
<path d="M146 46.1h3.8M146 45.2h3.8M147.9 43.3v1.9M147.9 46.1v2M162.7 53.3h3.8M162.7 52.4h3.8M164.6 50.5v1.9M164.6 53.3v1.9M218.7 45.2h1.9v5.7h-1.9zM218.7 59.6h1.9v5.6h-1.9zM201 62.9h3.8M201 61.9h3.8"/>
<path d="M202.9 60v1.9M202.9 62.9v1.9"/>
</g>
<g fill="none" stroke="#800000" stroke-width=".25">
<path d="M127.6 31.3h2.3M128.8 31.3v2.4M145.5 55.2h4.8M146.2 56h3.3M146.9 56.7h1.9M147.6 57.4h.5M147.9 52.9v2.3M162.2 72h4.8M162.9 72.7h3.4M163.7 73.4h1.9M164.4 74.1h.4M164.6 69.6v2.4"/>
<path d="M200.5 72h4.8M201.2 72.7h3.3M201.9 73.4h1.9M202.6 74.1h.5M202.9 69.6v2.4M217.2 72h4.8M217.9 72.7h3.4M218.6 73.4h2M219.4 74.1h.4M219.6 69.6v2.4"/>
</g>
<circle cx="210" cy="36.1" r=".48" fill="#000080"/>
<circle cx="210" cy="36.1" r=".48" fill="none" stroke="#000080" stroke-width=".2"/>
<path d="M210 36.1v2.4M210 43.3v2.4" fill="none" stroke="#000" stroke-width=".25"/>
<circle cx="210" cy="36.1" r=".48" fill="#000080"/>
<circle cx="210" cy="36.1" r=".48" fill="none" stroke="#000080" stroke-width=".2"/>
<path d="M210 38.5v1.9M226.3 35.2h5.7v1.9h-5.7zM208.2 41.4h3.7M208.2 40.4h3.7M210 41.4v1.9" fill="none" stroke="#00f" stroke-width=".25"/>
<path d="M237.5 31.3h2.4M238.7 31.3v2.4M207.7 48.1h4.7M208.4 48.8h3.3M209.1 49.5h1.9M209.8 50.2h.5M210 45.7v2.4" fill="none" stroke="#800000" stroke-width=".25"/>
<path d="M224.4 36.1h1.9M232.1 36.1h1.8" fill="none" stroke="#000" stroke-width=".25"/>
<path d="M57 33.7h19.2v21.5h-19.2z" fill-rule="evenodd" fill="#ffffb0"/>
<path d="M57 33.7h19.2v21.5h-19.2z" fill="none" stroke="#800000" stroke-width=".2"/>
<g fill="none" stroke="#000" stroke-width=".25">
<path d="M33.1 38.5v2.4M49.9 36.1h7.1M49.9 38.5h7.1M76.2 36.1h7.1M76.2 38.5h7.1M100.1 38.5v2.4M107.2 38.5v1.9M114.4 38.5v2.4M133.5 36.1h1.9M141.2 36.1h1.9M33.1 45.7v2.4M49.9 43.3h7.1"/>
<path d="M49.9 52.9h7.1M49.9 45.7h7.1M49.9 50.5h7.1M76.2 43.3h7.1M76.2 52.9h7.1M76.2 48.1h7.1M85.7 55.2v2.4M100.1 45.7v2.4M107.2 46.2v1.9M107.2 55.2v1.9M114.4 45.7v2.4M157.4 40.9v1.9"/>
<path d="M157.4 48.6v1.9M85.7 62.4v2.4M107.2 62.9v1.9M241.1 67.2v1.9M241.1 74.9v1.9"/>
</g>
<g fill="none" stroke="#800000" stroke-width=".25">
<path d="M12.8 31.3h2.4M14 31.3v2.4M118 31.3h2.4M119.2 31.3v2.4M30.7 52.9h4.8M31.4 53.6h3.4M32.2 54.3h1.9M32.9 55h.5M33.1 50.5v2.4M112 52.9h4.8M112.7 53.6h3.4M113.4 54.3h2"/>
<path d="M114.2 55h.4M114.4 50.5v2.4M155 55.2h4.8M155.8 56h3.3M156.5 56.7h1.9M157.2 57.4h.5M157.4 52.9v2.3M45.1 62.4h4.8M45.8 63.1h3.3M46.5 63.8h1.9M47.2 64.6h.5M47.5 60v2.4"/>
<path d="M83.3 69.6h4.8M84 70.3h3.4M84.8 71h1.9M85.5 71.7h.5M85.7 67.2v2.4M104.8 69.6h4.8M105.6 70.3h3.3M106.3 71h1.9M107 71.7h.5M107.2 67.2v2.4M239.9 64.8h2.4M241.1 64.8v2.4"/>
</g>
<g fill="none" stroke="#00f" stroke-width=".25">
<path d="M135.5 35.2h5.6v1.9h-5.6zM31.2 43.8h3.8M31.2 42.8h3.8M33.1 40.9v1.9M33.1 43.8v1.9M83.8 59.5h3.8M85.7 57.6v1.9M98.2 43.8h3.7M98.2 42.8h3.7M100.1 40.9v1.9M100.1 43.8v1.9M106.3 57.2h1.9v5.6h-1.9z"/>
<path d="M106.3 40.5h1.9v5.6h-1.9zM112.5 43.8h3.8M112.5 42.8h3.8M114.4 40.9v1.9M114.4 43.8v1.9M156.4 42.9h2v5.6h-2zM83.8 60.5h3.8M85.7 60.5v1.9M240.1 69.1h1.9v5.7h-1.9z"/>
</g>
<path d="M245.9 77.9h17.9l1.2 1.2-1.2 1.2h-17.9z" fill-rule="evenodd" fill="#ffff80"/>
<path d="M245.9 77.9h17.9l1.2 1.2-1.2 1.2h-17.9z" fill="none" stroke="#800000" stroke-width=".2"/>
<path d="M18.8 36.1h1.9M26.5 36.1h1.8" fill="none" stroke="#000" stroke-width=".25"/>
<path d="M20.7 35.2h5.7v1.9h-5.7z" fill="none" stroke="#00f" stroke-width=".25"/>
<circle cx="16.4" cy="36.1" r=".48" fill="#000080"/>
<circle cx="16.4" cy="36.1" r=".48" fill="none" stroke="#000080" stroke-width=".2"/>
<path d="M16.4 36.1v2.4" fill="none" stroke="#000" stroke-width=".25"/>
<circle cx="16.4" cy="36.1" r=".48" fill="#000080"/>
<circle cx="16.4" cy="36.1" r=".48" fill="none" stroke="#000080" stroke-width=".2"/>
<circle cx="16.4" cy="39.7" r="1.19" fill="none" stroke="#000" stroke-width=".25"/>
<circle cx="30.7" cy="36.1" r=".48" fill="#000080"/>
<circle cx="30.7" cy="36.1" r=".48" fill="none" stroke="#000080" stroke-width=".2"/>
<path d="M30.7 33.7v2.4" fill="none" stroke="#000" stroke-width=".25"/>
<circle cx="30.7" cy="36.1" r=".48" fill="#000080"/>
<circle cx="30.7" cy="36.1" r=".48" fill="none" stroke="#000080" stroke-width=".2"/>
<circle cx="30.7" cy="32.5" r="1.19" fill="none" stroke="#000" stroke-width=".25"/>
<circle cx="131.1" cy="36.1" r=".48" fill="#000080"/>
<circle cx="131.1" cy="36.1" r=".48" fill="none" stroke="#000080" stroke-width=".2"/>
<path d="M131.1 36.1v2.4" fill="none" stroke="#000" stroke-width=".25"/>
<circle cx="131.1" cy="36.1" r=".48" fill="#000080"/>
<circle cx="131.1" cy="36.1" r=".48" fill="none" stroke="#000080" stroke-width=".2"/>
<circle cx="131.1" cy="39.7" r="1.19" fill="none" stroke="#000" stroke-width=".25"/>
<circle cx="145.5" cy="36.1" r=".48" fill="#000080"/>
<circle cx="145.5" cy="36.1" r=".48" fill="none" stroke="#000080" stroke-width=".2"/>
<path d="M145.5 33.7v2.4" fill="none" stroke="#000" stroke-width=".25"/>
<circle cx="145.5" cy="36.1" r=".48" fill="#000080"/>
<circle cx="145.5" cy="36.1" r=".48" fill="none" stroke="#000080" stroke-width=".2"/>
<circle cx="145.5" cy="32.5" r="1.19" fill="none" stroke="#000" stroke-width=".25"/>
<circle cx="222" cy="36.1" r=".48" fill="#000080"/>
<circle cx="222" cy="36.1" r=".48" fill="none" stroke="#000080" stroke-width=".2"/>
<path d="M222 33.7v2.4" fill="none" stroke="#000" stroke-width=".25"/>
<circle cx="222" cy="36.1" r=".48" fill="#000080"/>
<circle cx="222" cy="36.1" r=".48" fill="none" stroke="#000080" stroke-width=".2"/>
<circle cx="222" cy="32.5" r="1.2" fill="none" stroke="#000" stroke-width=".25"/>
<circle cx="236.3" cy="36.1" r=".48" fill="#000080"/>
<circle cx="236.3" cy="36.1" r=".48" fill="none" stroke="#000080" stroke-width=".2"/>
<path d="M236.3 36.1v2.4" fill="none" stroke="#000" stroke-width=".25"/>
<circle cx="236.3" cy="36.1" r=".48" fill="#000080"/>
<circle cx="236.3" cy="36.1" r=".48" fill="none" stroke="#000080" stroke-width=".2"/>
<g fill="none" stroke="#000" stroke-width=".25">
<circle cx="236.3" cy="39.7" r="1.2"/>
<circle cx="236.3" cy="39.7" r="1.19"/>
</g>
<circle cx="236.3" cy="79.1" r=".48" fill="#000080"/>
<circle cx="236.3" cy="79.1" r=".48" fill="none" stroke="#000080" stroke-width=".2"/>
<path d="M236.3 76.8v2.3" fill="none" stroke="#000" stroke-width=".25"/>
<circle cx="236.3" cy="79.1" r=".48" fill="#000080"/>
<circle cx="236.3" cy="79.1" r=".48" fill="none" stroke="#000080" stroke-width=".2"/>
<g fill="none" stroke="#000" stroke-width=".25">
<circle cx="236.3" cy="75.6" r="1.2"/>
<circle cx="236.3" cy="75.6" r="1.19"/>
</g>
<circle cx="238.7" cy="81.5" r=".48" fill="#000080"/>
<circle cx="238.7" cy="81.5" r=".48" fill="none" stroke="#000080" stroke-width=".2"/>
<path d="M238.7 81.5v2.4" fill="none" stroke="#000" stroke-width=".25"/>
<circle cx="238.7" cy="81.5" r=".48" fill="#000080"/>
<circle cx="238.7" cy="81.5" r=".48" fill="none" stroke="#000080" stroke-width=".2"/>
<g fill="none" stroke="#000" stroke-width=".25">
<circle cx="238.7" cy="85.1" r="1.2"/>
<circle cx="238.7" cy="85.1" r="1.19"/>
</g>
<circle cx="253.1" cy="148.4" r=".48" fill="#000080"/>
<circle cx="253.1" cy="148.4" r=".48" fill="none" stroke="#000080" stroke-width=".2"/>
<path d="M253.1 146.1v2.3" fill="none" stroke="#000" stroke-width=".25"/>
<circle cx="253.1" cy="148.4" r=".48" fill="#000080"/>
<circle cx="253.1" cy="148.4" r=".48" fill="none" stroke="#000080" stroke-width=".2"/>
<circle cx="253.1" cy="144.9" r="1.19" fill="none" stroke="#000" stroke-width=".25"/>
<circle cx="233.9" cy="93.5" r=".48" fill="#000080"/>
<circle cx="233.9" cy="93.5" r=".48" fill="none" stroke="#000080" stroke-width=".2"/>
<path d="M233.9 91.1v2.4" fill="none" stroke="#000" stroke-width=".25"/>
<circle cx="233.9" cy="93.5" r=".48" fill="#000080"/>
<circle cx="233.9" cy="93.5" r=".48" fill="none" stroke="#000080" stroke-width=".2"/>
<g fill="none" stroke="#000" stroke-width=".25">
<circle cx="233.9" cy="89.9" r="1.19"/>
<circle cx="233.9" cy="89.9" r="1.2"/>
</g>
<circle cx="241.1" cy="110.2" r=".48" fill="#000080"/>
<circle cx="241.1" cy="110.2" r=".48" fill="none" stroke="#000080" stroke-width=".2"/>
<path d="M241.1 107.8v2.4" fill="none" stroke="#000" stroke-width=".25"/>
<circle cx="241.1" cy="110.2" r=".48" fill="#000080"/>
<circle cx="241.1" cy="110.2" r=".48" fill="none" stroke="#000080" stroke-width=".2"/>
<circle cx="241.1" cy="106.6" r="1.2" fill="none" stroke="#000" stroke-width=".25"/>
<circle cx="241.1" cy="112.6" r=".48" fill="#000080"/>
<circle cx="241.1" cy="112.6" r=".48" fill="none" stroke="#000080" stroke-width=".2"/>
<path d="M241.1 112.6v2.4" fill="none" stroke="#000" stroke-width=".25"/>
<circle cx="241.1" cy="112.6" r=".48" fill="#000080"/>
<circle cx="241.1" cy="112.6" r=".48" fill="none" stroke="#000080" stroke-width=".2"/>
<circle cx="241.1" cy="116.2" r="1.2" fill="none" stroke="#000" stroke-width=".25"/>
<circle cx="92.9" cy="170" r=".48" fill="#000080"/>
<circle cx="92.9" cy="170" r=".48" fill="none" stroke="#000080" stroke-width=".2"/>
<path d="M92.9 170v2.3" fill="none" stroke="#000" stroke-width=".25"/>
<circle cx="92.9" cy="170" r=".48" fill="#000080"/>
<circle cx="92.9" cy="170" r=".48" fill="none" stroke="#000080" stroke-width=".2"/>
<g fill="none" stroke="#000" stroke-width=".25">
<circle cx="92.9" cy="173.5" r="1.19"/>
<circle cx="92.9" cy="173.5" r="1.2"/>
</g>
<circle cx="92.9" cy="179.5" r=".48" fill="#000080"/>
<circle cx="92.9" cy="179.5" r=".48" fill="none" stroke="#000080" stroke-width=".2"/>
<path d="M92.9 179.5v2.4" fill="none" stroke="#000" stroke-width=".25"/>
<circle cx="92.9" cy="179.5" r=".48" fill="#000080"/>
<circle cx="92.9" cy="179.5" r=".48" fill="none" stroke="#000080" stroke-width=".2"/>
<g fill="none" stroke="#000" stroke-width=".25">
<circle cx="92.9" cy="183.1" r="1.2"/>
<circle cx="92.9" cy="183.1" r="1.19"/>
</g>
<circle cx="112" cy="36.1" r=".48" fill="#000080"/>
<circle cx="112" cy="36.1" r=".48" fill="none" stroke="#000080" stroke-width=".2"/>
<path d="M112 33.7v2.4" fill="none" stroke="#000" stroke-width=".25"/>
<circle cx="112" cy="36.1" r=".48" fill="#000080"/>
<circle cx="112" cy="36.1" r=".48" fill="none" stroke="#000080" stroke-width=".2"/>
<g fill="none" stroke="#000" stroke-width=".25">
<path d="M193.3 141.3v2.4M193.3 148.4v2.4M193.3 155.6v2.4M193.3 162.8v2.4"/>
<circle cx="112" cy="32.5" r="1.19"/>
</g>
<path d="M191.4 159.9h3.8M191.4 145.6h3.8M191.4 146.5h3.8M193.3 143.7v1.9M193.3 146.5v1.9M193.3 158v1.9M191.4 160.9h3.8M193.3 160.9v1.9" fill="none" stroke="#00f" stroke-width=".25"/>
<path d="M192.1 136.5h2.4M193.3 136.5v2.4M183.7 158h4.8M184.5 158.7h3.3M185.2 159.4h1.9M186.1 155.6v2.4M185.9 160.2h.5M192.1 170h2.4M193.3 167.6v2.4" fill="none" stroke="#800000" stroke-width=".25"/>
<path d="M205.3 129.3v2.4M42.7 155.6h-2.4v2.4" fill="none" stroke="#000080" stroke-width=".25"/>
<circle cx="42.7" cy="155.6" r=".48" fill="#000080"/>
<circle cx="42.7" cy="155.6" r=".48" fill="none" stroke="#000080" stroke-width=".2"/>
<path d="M42.7 153.2v2.4h2.4v2.4" fill="none" stroke="#000080" stroke-width=".25"/>
<circle cx="42.7" cy="155.6" r=".48" fill="#000080"/>
<circle cx="42.7" cy="155.6" r=".48" fill="none" stroke="#000080" stroke-width=".2"/>
<path d="M76.2 155.6h-2.4v2.4" fill="none" stroke="#000080" stroke-width=".25"/>
<circle cx="76.2" cy="155.6" r=".48" fill="#000080"/>
<circle cx="76.2" cy="155.6" r=".48" fill="none" stroke="#000080" stroke-width=".2"/>
<path d="M107.2 165.2h-2.4v2.4" fill="none" stroke="#000080" stroke-width=".25"/>
<circle cx="104.8" cy="165.2" r=".48" fill="#000080"/>
<circle cx="104.8" cy="165.2" r=".48" fill="none" stroke="#000080" stroke-width=".2"/>
<path d="M157.4 148.4h2.4M205.3 143.7h9.5" fill="none" stroke="#000080" stroke-width=".25"/>
<circle cx="205.3" cy="143.7" r=".48" fill="#000080"/>
<circle cx="205.3" cy="143.7" r=".48" fill="none" stroke="#000080" stroke-width=".2"/>
<path d="M248.3 148.4h2.4v21.6h-38.3v-16.8h2.4" fill="none" stroke="#000080" stroke-width=".25"/>
<circle cx="250.7" cy="148.4" r=".48" fill="#000080"/>
<circle cx="250.7" cy="148.4" r=".48" fill="none" stroke="#000080" stroke-width=".2"/>
<path d="M250.7 148.4h4.8" fill="none" stroke="#000080" stroke-width=".25"/>
<circle cx="250.7" cy="148.4" r=".48" fill="#000080"/>
<circle cx="250.7" cy="148.4" r=".48" fill="none" stroke="#000080" stroke-width=".2"/>
<circle cx="253.1" cy="148.4" r=".48" fill="#000080"/>
<circle cx="253.1" cy="148.4" r=".48" fill="none" stroke="#000080" stroke-width=".2"/>
<path d="M40.3 167.6v2.4" fill="none" stroke="#000080" stroke-width=".25"/>
<circle cx="40.3" cy="170" r=".48" fill="#000080"/>
<circle cx="40.3" cy="170" r=".48" fill="none" stroke="#000080" stroke-width=".2"/>
<path d="M45.1 167.6v11.9" fill="none" stroke="#000080" stroke-width=".25"/>
<circle cx="45.1" cy="179.5" r=".48" fill="#000080"/>
<circle cx="45.1" cy="179.5" r=".48" fill="none" stroke="#000080" stroke-width=".2"/>
<path d="M59.4 153.2v2.4" fill="none" stroke="#000080" stroke-width=".25"/>
<circle cx="59.4" cy="155.6" r=".48" fill="#000080"/>
<circle cx="59.4" cy="155.6" r=".48" fill="none" stroke="#000080" stroke-width=".2"/>
<path d="M73.8 167.6v2.4" fill="none" stroke="#000080" stroke-width=".25"/>
<circle cx="73.8" cy="170" r=".48" fill="#000080"/>
<circle cx="73.8" cy="170" r=".48" fill="none" stroke="#000080" stroke-width=".2"/>
<path d="M78.5 167.6v11.9" fill="none" stroke="#000080" stroke-width=".25"/>
<circle cx="78.5" cy="179.5" r=".48" fill="#000080"/>
<circle cx="78.5" cy="179.5" r=".48" fill="none" stroke="#000080" stroke-width=".2"/>
<path d="M88.1 146.1v2.3M88.1 158v2.4" fill="none" stroke="#000080" stroke-width=".25"/>
<circle cx="88.1" cy="146.1" r=".48" fill="#000080"/>
<circle cx="88.1" cy="146.1" r=".48" fill="none" stroke="#000080" stroke-width=".2"/>
<path d="M107.2 158h-2.4v7.2M205.3 155.6v2.4" fill="none" stroke="#000080" stroke-width=".25"/>
<circle cx="104.8" cy="165.2" r=".48" fill="#000080"/>
<circle cx="104.8" cy="165.2" r=".48" fill="none" stroke="#000080" stroke-width=".2"/>
<g fill="none" stroke="#000080" stroke-width=".25">
<path d="M33.1 119.8h12M33.1 112.6h12M33.1 115h12M33.1 110.2h12M33.1 103h12M33.1 105.4h12M80.9 119.8h12M80.9 112.6h12M80.9 115h12M80.9 110.2h12M80.9 103h12M80.9 105.4h12"/>
<path d="M128.8 119.8h11.9M128.8 112.6h11.9M128.8 115h11.9M128.8 110.2h11.9M128.8 103h11.9M128.8 105.4h11.9M176.6 119.8h11.9M176.6 112.6h11.9M176.6 115h11.9M176.6 110.2h11.9M176.6 103h11.9M176.6 105.4h11.9"/>
<path d="M226.8 110.2h19.1M145.5 153.2h2.4M145.5 158h2.4M145.5 148.4h2.4M157.4 153.2h2.4M157.4 158h2.4M169.4 153.2h9.6M169.4 158h9.6M169.4 148.4h9.6M145.5 162.8h2.4M157.4 162.8h2.4M169.4 162.8h9.6"/>
</g>
<circle cx="241.1" cy="110.2" r=".48" fill="#000080"/>
<circle cx="241.1" cy="110.2" r=".48" fill="none" stroke="#000080" stroke-width=".2"/>
<path d="M226.8 112.6h19.1" fill="none" stroke="#000080" stroke-width=".25"/>
<circle cx="241.1" cy="112.6" r=".48" fill="#000080"/>
<circle cx="241.1" cy="112.6" r=".48" fill="none" stroke="#000080" stroke-width=".2"/>
<g fill="none" stroke="#000080" stroke-width=".25">
<path d="M33.1 98.3h12M33.1 91.1h4.8M33.1 93.5h4.8M80.9 98.3h12M80.9 91.1h4.8M80.9 93.5h4.8M128.8 98.3h11.9M128.8 91.1h4.7M128.8 93.5h4.7M176.6 98.3h11.9M176.6 91.1h4.8M176.6 93.5h4.8"/>
<path d="M226.8 81.5h19.1"/>
</g>
<circle cx="238.7" cy="81.5" r=".48" fill="#000080"/>
<circle cx="238.7" cy="81.5" r=".48" fill="none" stroke="#000080" stroke-width=".2"/>
<path d="M226.8 93.5h19.1" fill="none" stroke="#000080" stroke-width=".25"/>
<circle cx="233.9" cy="93.5" r=".48" fill="#000080"/>
<circle cx="233.9" cy="93.5" r=".48" fill="none" stroke="#000080" stroke-width=".2"/>
<path d="M205.3 141.3v4.8" fill="none" stroke="#000080" stroke-width=".25"/>
<circle cx="205.3" cy="143.7" r=".48" fill="#000080"/>
<circle cx="205.3" cy="143.7" r=".48" fill="none" stroke="#000080" stroke-width=".2"/>
<path d="M167 62.4h-2.4v2.4h2.4" fill="none" stroke="#000080" stroke-width=".25"/>
<circle cx="164.6" cy="64.8" r=".48" fill="#000080"/>
<circle cx="164.6" cy="64.8" r=".48" fill="none" stroke="#000080" stroke-width=".2"/>
<path d="M164.6 57.6h2.4M164.6 48.1h2.4M200.5 48.1h2.4v7.1h16.7v2.4M200.5 57.6h2.4" fill="none" stroke="#000080" stroke-width=".25"/>
<circle cx="219.6" cy="55.2" r=".48" fill="#000080"/>
<circle cx="219.6" cy="55.2" r=".48" fill="none" stroke="#000080" stroke-width=".2"/>
<path d="M238.7 33.7v2.4h-4.8" fill="none" stroke="#000080" stroke-width=".25"/>
<circle cx="236.3" cy="36.1" r=".48" fill="#000080"/>
<circle cx="236.3" cy="36.1" r=".48" fill="none" stroke="#000080" stroke-width=".2"/>
<path d="M147.9 36.1v4.8M147.9 50.5v2.4" fill="none" stroke="#000080" stroke-width=".25"/>
<circle cx="147.9" cy="36.1" r=".48" fill="#000080"/>
<circle cx="147.9" cy="36.1" r=".48" fill="none" stroke="#000080" stroke-width=".2"/>
<path d="M164.6 64.8v4.8" fill="none" stroke="#000080" stroke-width=".25"/>
<circle cx="164.6" cy="64.8" r=".48" fill="#000080"/>
<circle cx="164.6" cy="64.8" r=".48" fill="none" stroke="#000080" stroke-width=".2"/>
<path d="M219.6 52.9v2.3M202.9 67.2v2.4M219.6 67.2v2.4" fill="none" stroke="#000080" stroke-width=".25"/>
<circle cx="219.6" cy="55.2" r=".48" fill="#000080"/>
<circle cx="219.6" cy="55.2" r=".48" fill="none" stroke="#000080" stroke-width=".2"/>
<path d="M219.6 36.1v7.2" fill="none" stroke="#000080" stroke-width=".25"/>
<circle cx="219.6" cy="36.1" r=".48" fill="#000080"/>
<circle cx="219.6" cy="36.1" r=".48" fill="none" stroke="#000080" stroke-width=".2"/>
<path d="M200.5 36.1h23.9" fill="none" stroke="#000080" stroke-width=".25"/>
<circle cx="210" cy="36.1" r=".48" fill="#000080"/>
<circle cx="210" cy="36.1" r=".48" fill="none" stroke="#000080" stroke-width=".2"/>
<circle cx="219.6" cy="36.1" r=".48" fill="#000080"/>
<circle cx="219.6" cy="36.1" r=".48" fill="none" stroke="#000080" stroke-width=".2"/>
<circle cx="222" cy="36.1" r=".48" fill="#000080"/>
<circle cx="222" cy="36.1" r=".48" fill="none" stroke="#000080" stroke-width=".2"/>
<path d="M49.9 50.5h-2.4v2.4h2.4" fill="none" stroke="#000080" stroke-width=".25"/>
<circle cx="47.5" cy="52.8" r=".48" fill="#000080"/>
<circle cx="47.5" cy="52.8" r=".48" fill="none" stroke="#000080" stroke-width=".2"/>
<path d="M47.5 52.9v7.1" fill="none" stroke="#000080" stroke-width=".25"/>
<circle cx="47.5" cy="52.8" r=".48" fill="#000080"/>
<circle cx="47.5" cy="52.8" r=".48" fill="none" stroke="#000080" stroke-width=".2"/>
<path d="M47.5 36.1v2.4h2.4M167 38.5h-9.6v2.4M157.4 50.5v2.4" fill="none" stroke="#000080" stroke-width=".25"/>
<circle cx="47.5" cy="38.5" r=".48" fill="#000080"/>
<circle cx="47.5" cy="38.5" r=".48" fill="none" stroke="#000080" stroke-width=".2"/>
<circle cx="47.5" cy="36.1" r=".48" fill="#000080"/>
<circle cx="47.5" cy="36.1" r=".48" fill="none" stroke="#000080" stroke-width=".2"/>
<path d="M47.5 38.5v4.8h2.4" fill="none" stroke="#000080" stroke-width=".25"/>
<circle cx="47.5" cy="38.5" r=".48" fill="#000080"/>
<circle cx="47.5" cy="38.5" r=".48" fill="none" stroke="#000080" stroke-width=".2"/>
<path d="M83.3 52.9h2.4v2.3M100.1 48.1v2.4M85.7 64.8v2.4" fill="none" stroke="#000080" stroke-width=".25"/>
<circle cx="100.1" cy="50.5" r=".48" fill="#000080"/>
<circle cx="100.1" cy="50.5" r=".48" fill="none" stroke="#000080" stroke-width=".2"/>
<path d="M83.3 36.1h12v2.4h-12" fill="none" stroke="#000080" stroke-width=".25"/>
<circle cx="95.3" cy="36.1" r=".48" fill="#000080"/>
<circle cx="95.3" cy="36.1" r=".48" fill="none" stroke="#000080" stroke-width=".2"/>
<path d="M100.1 36.1v2.4M114.4 48.1v2.4M107.2 64.8v2.4" fill="none" stroke="#000080" stroke-width=".25"/>
<circle cx="100.1" cy="36.1" r=".48" fill="#000080"/>
<circle cx="100.1" cy="36.1" r=".48" fill="none" stroke="#000080" stroke-width=".2"/>
<path d="M107.2 48.1v2.4" fill="none" stroke="#000080" stroke-width=".25"/>
<circle cx="107.2" cy="50.5" r=".48" fill="#000080"/>
<circle cx="107.2" cy="50.5" r=".48" fill="none" stroke="#000080" stroke-width=".2"/>
<path d="M107.2 36.1v2.4" fill="none" stroke="#000080" stroke-width=".25"/>
<circle cx="107.2" cy="36.1" r=".48" fill="#000080"/>
<circle cx="107.2" cy="36.1" r=".48" fill="none" stroke="#000080" stroke-width=".2"/>
<path d="M33.1 179.5h16.8" fill="none" stroke="#000080" stroke-width=".25"/>
<circle cx="45.1" cy="179.5" r=".48" fill="#000080"/>
<circle cx="45.1" cy="179.5" r=".48" fill="none" stroke="#000080" stroke-width=".2"/>
<path d="M33.1 170h26.3" fill="none" stroke="#000080" stroke-width=".25"/>
<circle cx="40.3" cy="170" r=".48" fill="#000080"/>
<circle cx="40.3" cy="170" r=".48" fill="none" stroke="#000080" stroke-width=".2"/>
<path d="M64.2 162.8v-7.2h-9.6v16.7" fill="none" stroke="#000080" stroke-width=".25"/>
<circle cx="59.4" cy="155.6" r=".48" fill="#000080"/>
<circle cx="59.4" cy="155.6" r=".48" fill="none" stroke="#000080" stroke-width=".2"/>
<path d="M107.2 153.2h-7.1v26.3h-40.7" fill="none" stroke="#000080" stroke-width=".25"/>
<circle cx="78.5" cy="179.5" r=".48" fill="#000080"/>
<circle cx="78.5" cy="179.5" r=".48" fill="none" stroke="#000080" stroke-width=".2"/>
<circle cx="92.9" cy="179.5" r=".48" fill="#000080"/>
<circle cx="92.9" cy="179.5" r=".48" fill="none" stroke="#000080" stroke-width=".2"/>
<path d="M107.2 150.8h-9.5v19.2h-28.7" fill="none" stroke="#000080" stroke-width=".25"/>
<circle cx="92.9" cy="170" r=".48" fill="#000080"/>
<circle cx="92.9" cy="170" r=".48" fill="none" stroke="#000080" stroke-width=".2"/>
<circle cx="73.8" cy="170" r=".48" fill="#000080"/>
<circle cx="73.8" cy="170" r=".48" fill="none" stroke="#000080" stroke-width=".2"/>
<path d="M76.2 143.7v11.9h2.3v2.4" fill="none" stroke="#000080" stroke-width=".25"/>
<circle cx="76.2" cy="146.1" r=".48" fill="#000080"/>
<circle cx="76.2" cy="146.1" r=".48" fill="none" stroke="#000080" stroke-width=".2"/>
<circle cx="76.2" cy="155.6" r=".48" fill="#000080"/>
<circle cx="76.2" cy="155.6" r=".48" fill="none" stroke="#000080" stroke-width=".2"/>
<path d="M76.2 146.1h31" fill="none" stroke="#000080" stroke-width=".25"/>
<circle cx="88.1" cy="146.1" r=".48" fill="#000080"/>
<circle cx="88.1" cy="146.1" r=".48" fill="none" stroke="#000080" stroke-width=".2"/>
<circle cx="76.2" cy="146.1" r=".48" fill="#000080"/>
<circle cx="76.2" cy="146.1" r=".48" fill="none" stroke="#000080" stroke-width=".2"/>
<path d="M128.8 33.7v2.4h4.7" fill="none" stroke="#000080" stroke-width=".25"/>
<circle cx="131.1" cy="36.1" r=".48" fill="#000080"/>
<circle cx="131.1" cy="36.1" r=".48" fill="none" stroke="#000080" stroke-width=".2"/>
<path d="M147.9 36.1h19.1" fill="none" stroke="#000080" stroke-width=".25"/>
<circle cx="147.9" cy="36.1" r=".48" fill="#000080"/>
<circle cx="147.9" cy="36.1" r=".48" fill="none" stroke="#000080" stroke-width=".2"/>
<path d="M83.3 48.1h7.2M241.1 76.8v2.3" fill="none" stroke="#000080" stroke-width=".25"/>
<circle cx="241.1" cy="79.1" r=".48" fill="#000080"/>
<circle cx="241.1" cy="79.1" r=".48" fill="none" stroke="#000080" stroke-width=".2"/>
<path d="M119.2 33.7v2.4h-4.8" fill="none" stroke="#000080" stroke-width=".25"/>
<circle cx="114.4" cy="36.1" r=".48" fill="#000080"/>
<circle cx="114.4" cy="36.1" r=".48" fill="none" stroke="#000080" stroke-width=".2"/>
<path d="M83.3 43.3h12v7.2h11.9v4.7" fill="none" stroke="#000080" stroke-width=".25"/>
<circle cx="107.2" cy="50.5" r=".48" fill="#000080"/>
<circle cx="107.2" cy="50.5" r=".48" fill="none" stroke="#000080" stroke-width=".2"/>
<circle cx="100.1" cy="50.5" r=".48" fill="#000080"/>
<circle cx="100.1" cy="50.5" r=".48" fill="none" stroke="#000080" stroke-width=".2"/>
<path d="M47.5 36.1h2.4" fill="none" stroke="#000080" stroke-width=".25"/>
<circle cx="47.5" cy="36.1" r=".48" fill="#000080"/>
<circle cx="47.5" cy="36.1" r=".48" fill="none" stroke="#000080" stroke-width=".2"/>
<path d="M28.3 36.1h4.8" fill="none" stroke="#000080" stroke-width=".25"/>
<circle cx="30.7" cy="36.1" r=".48" fill="#000080"/>
<circle cx="30.7" cy="36.1" r=".48" fill="none" stroke="#000080" stroke-width=".2"/>
<circle cx="33.1" cy="36.1" r=".48" fill="#000080"/>
<circle cx="33.1" cy="36.1" r=".48" fill="none" stroke="#000080" stroke-width=".2"/>
<path d="M33.1 36.1h14.4" fill="none" stroke="#000080" stroke-width=".25"/>
<circle cx="33.1" cy="36.1" r=".48" fill="#000080"/>
<circle cx="33.1" cy="36.1" r=".48" fill="none" stroke="#000080" stroke-width=".2"/>
<circle cx="47.5" cy="36.1" r=".48" fill="#000080"/>
<circle cx="47.5" cy="36.1" r=".48" fill="none" stroke="#000080" stroke-width=".2"/>
<path d="M95.3 36.1h19.1v2.4" fill="none" stroke="#000080" stroke-width=".25"/>
<circle cx="95.3" cy="36.1" r=".48" fill="#000080"/>
<circle cx="95.3" cy="36.1" r=".48" fill="none" stroke="#000080" stroke-width=".2"/>
<circle cx="100.1" cy="36.1" r=".48" fill="#000080"/>
<circle cx="100.1" cy="36.1" r=".48" fill="none" stroke="#000080" stroke-width=".2"/>
<circle cx="107.2" cy="36.1" r=".48" fill="#000080"/>
<circle cx="107.2" cy="36.1" r=".48" fill="none" stroke="#000080" stroke-width=".2"/>
<circle cx="112" cy="36.1" r=".48" fill="#000080"/>
<circle cx="112" cy="36.1" r=".48" fill="none" stroke="#000080" stroke-width=".2"/>
<circle cx="114.4" cy="36.1" r=".48" fill="#000080"/>
<circle cx="114.4" cy="36.1" r=".48" fill="none" stroke="#000080" stroke-width=".2"/>
<path d="M14 33.7v2.4h4.8" fill="none" stroke="#000080" stroke-width=".25"/>
<circle cx="16.4" cy="36.1" r=".48" fill="#000080"/>
<circle cx="16.4" cy="36.1" r=".48" fill="none" stroke="#000080" stroke-width=".2"/>
<path d="M33.1 36.1v2.4M33.1 48.1v2.4" fill="none" stroke="#000080" stroke-width=".25"/>
<circle cx="33.1" cy="36.1" r=".48" fill="#000080"/>
<circle cx="33.1" cy="36.1" r=".48" fill="none" stroke="#000080" stroke-width=".2"/>
<path d="M143.1 36.1h4.8" fill="none" stroke="#000080" stroke-width=".25"/>
<circle cx="147.9" cy="36.1" r=".48" fill="#000080"/>
<circle cx="147.9" cy="36.1" r=".48" fill="none" stroke="#000080" stroke-width=".2"/>
<circle cx="145.5" cy="36.1" r=".48" fill="#000080"/>
<circle cx="145.5" cy="36.1" r=".48" fill="none" stroke="#000080" stroke-width=".2"/>
<path d="M226.8 79.1h19.1" fill="none" stroke="#000080" stroke-width=".25"/>
<circle cx="236.3" cy="79.1" r=".48" fill="#000080"/>
<circle cx="236.3" cy="79.1" r=".48" fill="none" stroke="#000080" stroke-width=".2"/>
<circle cx="241.1" cy="79.1" r=".48" fill="#000080"/>
<circle cx="241.1" cy="79.1" r=".48" fill="none" stroke="#000080" stroke-width=".2"/>
<path d="M193.3 138.9v2.4M193.3 150.8v4.8M193.3 165.2v2.4" fill="none" stroke="#000080" stroke-width=".25"/>
<circle cx="193.3" cy="153.2" r=".48" fill="#000080"/>
<circle cx="193.3" cy="153.2" r=".48" fill="none" stroke="#000080" stroke-width=".2"/>
<path d="M193.3 153.2h-7.2v2.4" fill="none" stroke="#000080" stroke-width=".25"/>
<circle cx="193.3" cy="153.2" r=".48" fill="#000080"/>
<circle cx="193.3" cy="153.2" r=".48" fill="none" stroke="#000080" stroke-width=".2"/>
<path d="M226.8 98.3h19.1M226.8 100.7h19.1M226.8 122.2h19.1" fill="none" stroke="#000080" stroke-width=".67"/>
<path d="M40.3 45.7h9.6" fill="none" stroke="#000080" stroke-width=".25"/>
<use href="#words"/>
</svg>
